VERSION 5.7 ;
BUSBITCHARS "[]" ;
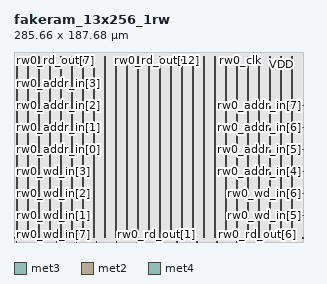
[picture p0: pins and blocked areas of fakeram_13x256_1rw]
MACRO fakeram_13x256_1rw
  FOREIGN fakeram_13x256_1rw 0 0 ;
  SYMMETRY X Y R90 ;
  SIZE 285.660 BY 187.680 ;
  CLASS BLOCK ;
  PIN rw0_wd_in[0]
    DIRECTION INPUT ;
    USE SIGNAL ;
    SHAPE ABUTMENT ;
    PORT
      LAYER met3 ;
      RECT 0.000 3.930 0.900 4.230 ;
    END
  END rw0_wd_in[0]
  PIN rw0_wd_in[1]
    DIRECTION INPUT ;
    USE SIGNAL ;
    SHAPE ABUTMENT ;
    PORT
      LAYER met3 ;
      RECT 0.000 25.690 0.900 25.990 ;
    END
  END rw0_wd_in[1]
  PIN rw0_wd_in[2]
    DIRECTION INPUT ;
    USE SIGNAL ;
    SHAPE ABUTMENT ;
    PORT
      LAYER met3 ;
      RECT 0.000 47.450 0.900 47.750 ;
    END
  END rw0_wd_in[2]
  PIN rw0_wd_in[3]
    DIRECTION INPUT ;
    USE SIGNAL ;
    SHAPE ABUTMENT ;
    PORT
      LAYER met3 ;
      RECT 0.000 69.210 0.900 69.510 ;
    END
  END rw0_wd_in[3]
  PIN rw0_wd_in[4]
    DIRECTION INPUT ;
    USE SIGNAL ;
    SHAPE ABUTMENT ;
    PORT
      LAYER met3 ;
      RECT 284.760 3.930 285.660 4.230 ;
    END
  END rw0_wd_in[4]
  PIN rw0_wd_in[5]
    DIRECTION INPUT ;
    USE SIGNAL ;
    SHAPE ABUTMENT ;
    PORT
      LAYER met3 ;
      RECT 284.760 25.690 285.660 25.990 ;
    END
  END rw0_wd_in[5]
  PIN rw0_wd_in[6]
    DIRECTION INPUT ;
    USE SIGNAL ;
    SHAPE ABUTMENT ;
    PORT
      LAYER met3 ;
      RECT 284.760 47.450 285.660 47.750 ;
    END
  END rw0_wd_in[6]
  PIN rw0_wd_in[7]
    DIRECTION OUTPUT ;
    USE SIGNAL ;
    SHAPE ABUTMENT ;
    PORT
      LAYER met2 ;
      RECT 2.690 0.000 2.830 0.420 ;
    END
  END rw0_wd_in[7]
  PIN rw0_wd_in[8]
    DIRECTION OUTPUT ;
    USE SIGNAL ;
    SHAPE ABUTMENT ;
    PORT
      LAYER met2 ;
      RECT 22.470 0.000 22.610 0.420 ;
    END
  END rw0_wd_in[8]
  PIN rw0_wd_in[9]
    DIRECTION OUTPUT ;
    USE SIGNAL ;
    SHAPE ABUTMENT ;
    PORT
      LAYER met2 ;
      RECT 42.250 0.000 42.390 0.420 ;
    END
  END rw0_wd_in[9]
  PIN rw0_wd_in[10]
    DIRECTION OUTPUT ;
    USE SIGNAL ;
    SHAPE ABUTMENT ;
    PORT
      LAYER met2 ;
      RECT 62.030 0.000 62.170 0.420 ;
    END
  END rw0_wd_in[10]
  PIN rw0_wd_in[11]
    DIRECTION OUTPUT ;
    USE SIGNAL ;
    SHAPE ABUTMENT ;
    PORT
      LAYER met2 ;
      RECT 81.810 0.000 81.950 0.420 ;
    END
  END rw0_wd_in[11]
  PIN rw0_wd_in[12]
    DIRECTION OUTPUT ;
    USE SIGNAL ;
    SHAPE ABUTMENT ;
    PORT
      LAYER met2 ;
      RECT 101.590 0.000 101.730 0.420 ;
    END
  END rw0_wd_in[12]
  PIN rw0_rd_out[0]
    DIRECTION OUTPUT ;
    USE SIGNAL ;
    SHAPE ABUTMENT ;
    PORT
      LAYER met2 ;
      RECT 121.370 0.000 121.510 0.420 ;
    END
  END rw0_rd_out[0]
  PIN rw0_rd_out[1]
    DIRECTION OUTPUT ;
    USE SIGNAL ;
    SHAPE ABUTMENT ;
    PORT
      LAYER met2 ;
      RECT 141.150 0.000 141.290 0.420 ;
    END
  END rw0_rd_out[1]
  PIN rw0_rd_out[2]
    DIRECTION OUTPUT ;
    USE SIGNAL ;
    SHAPE ABUTMENT ;
    PORT
      LAYER met2 ;
      RECT 160.930 0.000 161.070 0.420 ;
    END
  END rw0_rd_out[2]
  PIN rw0_rd_out[3]
    DIRECTION OUTPUT ;
    USE SIGNAL ;
    SHAPE ABUTMENT ;
    PORT
      LAYER met2 ;
      RECT 180.710 0.000 180.850 0.420 ;
    END
  END rw0_rd_out[3]
  PIN rw0_rd_out[4]
    DIRECTION OUTPUT ;
    USE SIGNAL ;
    SHAPE ABUTMENT ;
    PORT
      LAYER met2 ;
      RECT 200.490 0.000 200.630 0.420 ;
    END
  END rw0_rd_out[4]
  PIN rw0_rd_out[5]
    DIRECTION OUTPUT ;
    USE SIGNAL ;
    SHAPE ABUTMENT ;
    PORT
      LAYER met2 ;
      RECT 220.270 0.000 220.410 0.420 ;
    END
  END rw0_rd_out[5]
  PIN rw0_rd_out[6]
    DIRECTION OUTPUT ;
    USE SIGNAL ;
    SHAPE ABUTMENT ;
    PORT
      LAYER met2 ;
      RECT 240.050 0.000 240.190 0.420 ;
    END
  END rw0_rd_out[6]
  PIN rw0_rd_out[7]
    DIRECTION OUTPUT ;
    USE SIGNAL ;
    SHAPE ABUTMENT ;
    PORT
      LAYER met2 ;
      RECT 2.690 187.260 2.830 187.680 ;
    END
  END rw0_rd_out[7]
  PIN rw0_rd_out[8]
    DIRECTION OUTPUT ;
    USE SIGNAL ;
    SHAPE ABUTMENT ;
    PORT
      LAYER met2 ;
      RECT 30.290 187.260 30.430 187.680 ;
    END
  END rw0_rd_out[8]
  PIN rw0_rd_out[9]
    DIRECTION OUTPUT ;
    USE SIGNAL ;
    SHAPE ABUTMENT ;
    PORT
      LAYER met2 ;
      RECT 57.890 187.260 58.030 187.680 ;
    END
  END rw0_rd_out[9]
  PIN rw0_rd_out[10]
    DIRECTION OUTPUT ;
    USE SIGNAL ;
    SHAPE ABUTMENT ;
    PORT
      LAYER met2 ;
      RECT 85.490 187.260 85.630 187.680 ;
    END
  END rw0_rd_out[10]
  PIN rw0_rd_out[11]
    DIRECTION OUTPUT ;
    USE SIGNAL ;
    SHAPE ABUTMENT ;
    PORT
      LAYER met2 ;
      RECT 113.090 187.260 113.230 187.680 ;
    END
  END rw0_rd_out[11]
  PIN rw0_rd_out[12]
    DIRECTION OUTPUT ;
    USE SIGNAL ;
    SHAPE ABUTMENT ;
    PORT
      LAYER met2 ;
      RECT 140.690 187.260 140.830 187.680 ;
    END
  END rw0_rd_out[12]
  PIN rw0_addr_in[0]
    DIRECTION INPUT ;
    USE SIGNAL ;
    SHAPE ABUTMENT ;
    PORT
      LAYER met3 ;
      RECT 0.000 90.970 0.900 91.270 ;
    END
  END rw0_addr_in[0]
  PIN rw0_addr_in[1]
    DIRECTION INPUT ;
    USE SIGNAL ;
    SHAPE ABUTMENT ;
    PORT
      LAYER met3 ;
      RECT 0.000 112.730 0.900 113.030 ;
    END
  END rw0_addr_in[1]
  PIN rw0_addr_in[2]
    DIRECTION INPUT ;
    USE SIGNAL ;
    SHAPE ABUTMENT ;
    PORT
      LAYER met3 ;
      RECT 0.000 134.490 0.900 134.790 ;
    END
  END rw0_addr_in[2]
  PIN rw0_addr_in[3]
    DIRECTION INPUT ;
    USE SIGNAL ;
    SHAPE ABUTMENT ;
    PORT
      LAYER met3 ;
      RECT 0.000 156.250 0.900 156.550 ;
    END
  END rw0_addr_in[3]
  PIN rw0_addr_in[4]
    DIRECTION INPUT ;
    USE SIGNAL ;
    SHAPE ABUTMENT ;
    PORT
      LAYER met3 ;
      RECT 284.760 69.210 285.660 69.510 ;
    END
  END rw0_addr_in[4]
  PIN rw0_addr_in[5]
    DIRECTION INPUT ;
    USE SIGNAL ;
    SHAPE ABUTMENT ;
    PORT
      LAYER met3 ;
      RECT 284.760 90.970 285.660 91.270 ;
    END
  END rw0_addr_in[5]
  PIN rw0_addr_in[6]
    DIRECTION INPUT ;
    USE SIGNAL ;
    SHAPE ABUTMENT ;
    PORT
      LAYER met3 ;
      RECT 284.760 112.730 285.660 113.030 ;
    END
  END rw0_addr_in[6]
  PIN rw0_addr_in[7]
    DIRECTION INPUT ;
    USE SIGNAL ;
    SHAPE ABUTMENT ;
    PORT
      LAYER met3 ;
      RECT 284.760 134.490 285.660 134.790 ;
    END
  END rw0_addr_in[7]
  PIN rw0_we_in
    DIRECTION INPUT ;
    USE SIGNAL ;
    SHAPE ABUTMENT ;
    PORT
      LAYER met2 ;
      RECT 168.290 187.260 168.430 187.680 ;
    END
  END rw0_we_in
  PIN rw0_ce_in
    DIRECTION INPUT ;
    USE SIGNAL ;
    SHAPE ABUTMENT ;
    PORT
      LAYER met2 ;
      RECT 195.890 187.260 196.030 187.680 ;
    END
  END rw0_ce_in
  PIN rw0_clk
    DIRECTION INPUT ;
    USE SIGNAL ;
    SHAPE ABUTMENT ;
    PORT
      LAYER met2 ;
      RECT 223.490 187.260 223.630 187.680 ;
    END
  END rw0_clk
  PIN VSS
    DIRECTION INOUT ;
    USE GROUND ;
    PORT
      LAYER met4 ;
      RECT 2.160 4.080 3.360 183.600 ;
      RECT 13.040 4.080 14.240 183.600 ;
      RECT 23.920 4.080 25.120 183.600 ;
      RECT 34.800 4.080 36.000 183.600 ;
      RECT 45.680 4.080 46.880 183.600 ;
      RECT 56.560 4.080 57.760 183.600 ;
      RECT 67.440 4.080 68.640 183.600 ;
      RECT 78.320 4.080 79.520 183.600 ;
      RECT 89.200 4.080 90.400 183.600 ;
      RECT 100.080 4.080 101.280 183.600 ;
      RECT 110.960 4.080 112.160 183.600 ;
      RECT 121.840 4.080 123.040 183.600 ;
      RECT 132.720 4.080 133.920 183.600 ;
      RECT 143.600 4.080 144.800 183.600 ;
      RECT 154.480 4.080 155.680 183.600 ;
      RECT 165.360 4.080 166.560 183.600 ;
      RECT 176.240 4.080 177.440 183.600 ;
      RECT 187.120 4.080 188.320 183.600 ;
      RECT 198.000 4.080 199.200 183.600 ;
      RECT 208.880 4.080 210.080 183.600 ;
      RECT 219.760 4.080 220.960 183.600 ;
      RECT 230.640 4.080 231.840 183.600 ;
      RECT 241.520 4.080 242.720 183.600 ;
      RECT 252.400 4.080 253.600 183.600 ;
      RECT 263.280 4.080 264.480 183.600 ;
      RECT 274.160 4.080 275.360 183.600 ;
    END
  END VSS
  PIN VDD
    DIRECTION INOUT ;
    USE POWER ;
    PORT
      LAYER met4 ;
      RECT 2.160 4.080 3.360 183.600 ;
      RECT 13.040 4.080 14.240 183.600 ;
      RECT 23.920 4.080 25.120 183.600 ;
      RECT 34.800 4.080 36.000 183.600 ;
      RECT 45.680 4.080 46.880 183.600 ;
      RECT 56.560 4.080 57.760 183.600 ;
      RECT 67.440 4.080 68.640 183.600 ;
      RECT 78.320 4.080 79.520 183.600 ;
      RECT 89.200 4.080 90.400 183.600 ;
      RECT 100.080 4.080 101.280 183.600 ;
      RECT 110.960 4.080 112.160 183.600 ;
      RECT 121.840 4.080 123.040 183.600 ;
      RECT 132.720 4.080 133.920 183.600 ;
      RECT 143.600 4.080 144.800 183.600 ;
      RECT 154.480 4.080 155.680 183.600 ;
      RECT 165.360 4.080 166.560 183.600 ;
      RECT 176.240 4.080 177.440 183.600 ;
      RECT 187.120 4.080 188.320 183.600 ;
      RECT 198.000 4.080 199.200 183.600 ;
      RECT 208.880 4.080 210.080 183.600 ;
      RECT 219.760 4.080 220.960 183.600 ;
      RECT 230.640 4.080 231.840 183.600 ;
      RECT 241.520 4.080 242.720 183.600 ;
      RECT 252.400 4.080 253.600 183.600 ;
      RECT 263.280 4.080 264.480 183.600 ;
      RECT 274.160 4.080 275.360 183.600 ;
    END
  END VDD
  OBS
    LAYER met1 ;
    RECT 0 0 285.660 187.680 ;
    LAYER met2 ;
    RECT 0 0 285.660 187.680 ;
    LAYER met3 ;
    RECT 0 0 285.660 187.680 ;
    LAYER met4 ;
    RECT 0 0 285.660 187.680 ;
  END
END fakeram_13x256_1rw

END LIBRARY
